VERSION 5.7 ;
  NOWIREEXTENSIONATPIN ON ;
  DIVIDERCHAR "/" ;
  BUSBITCHARS "[]" ;
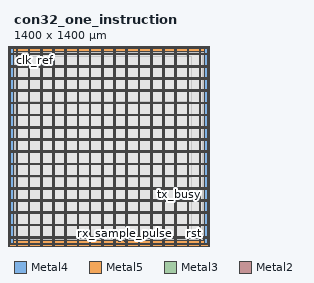
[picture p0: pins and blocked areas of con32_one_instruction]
MACRO con32_one_instruction
  CLASS BLOCK ;
  FOREIGN con32_one_instruction ;
  ORIGIN 0.000 0.000 ;
  SIZE 1400.000 BY 1400.000 ;
  PIN VDD
    DIRECTION INOUT ;
    USE POWER ;
    PORT
      LAYER Metal4 ;
        RECT -24.880 -18.160 -4.880 1417.600 ;
    END
    PORT
      LAYER Metal4 ;
        RECT 1404.880 -18.160 1424.880 1417.600 ;
    END
    PORT
      LAYER Metal5 ;
        RECT -24.880 -18.160 1424.880 1.840 ;
    END
    PORT
      LAYER Metal5 ;
        RECT -24.880 1397.600 1424.880 1417.600 ;
    END
    PORT
      LAYER Metal4 ;
        RECT 14.940 -42.960 19.940 1442.400 ;
    END
    PORT
      LAYER Metal4 ;
        RECT 104.940 -42.960 109.940 1442.400 ;
    END
    PORT
      LAYER Metal4 ;
        RECT 194.940 -42.960 199.940 1442.400 ;
    END
    PORT
      LAYER Metal4 ;
        RECT 284.940 -42.960 289.940 1442.400 ;
    END
    PORT
      LAYER Metal4 ;
        RECT 374.940 -42.960 379.940 1442.400 ;
    END
    PORT
      LAYER Metal4 ;
        RECT 464.940 -42.960 469.940 1442.400 ;
    END
    PORT
      LAYER Metal4 ;
        RECT 554.940 -42.960 559.940 1442.400 ;
    END
    PORT
      LAYER Metal4 ;
        RECT 644.940 -42.960 649.940 1442.400 ;
    END
    PORT
      LAYER Metal4 ;
        RECT 734.940 -42.960 739.940 1442.400 ;
    END
    PORT
      LAYER Metal4 ;
        RECT 824.940 -42.960 829.940 1442.400 ;
    END
    PORT
      LAYER Metal4 ;
        RECT 914.940 -42.960 919.940 1442.400 ;
    END
    PORT
      LAYER Metal4 ;
        RECT 1004.940 -42.960 1009.940 1442.400 ;
    END
    PORT
      LAYER Metal4 ;
        RECT 1094.940 -42.960 1099.940 1442.400 ;
    END
    PORT
      LAYER Metal4 ;
        RECT 1184.940 -42.960 1189.940 1442.400 ;
    END
    PORT
      LAYER Metal4 ;
        RECT 1274.940 -42.960 1279.940 1442.400 ;
    END
    PORT
      LAYER Metal4 ;
        RECT 1364.940 -42.960 1369.940 1442.400 ;
    END
    PORT
      LAYER Metal5 ;
        RECT -49.680 21.990 1449.680 26.990 ;
    END
    PORT
      LAYER Metal5 ;
        RECT -49.680 111.990 1449.680 116.990 ;
    END
    PORT
      LAYER Metal5 ;
        RECT -49.680 201.990 1449.680 206.990 ;
    END
    PORT
      LAYER Metal5 ;
        RECT -49.680 291.990 1449.680 296.990 ;
    END
    PORT
      LAYER Metal5 ;
        RECT -49.680 381.990 1449.680 386.990 ;
    END
    PORT
      LAYER Metal5 ;
        RECT -49.680 471.990 1449.680 476.990 ;
    END
    PORT
      LAYER Metal5 ;
        RECT -49.680 561.990 1449.680 566.990 ;
    END
    PORT
      LAYER Metal5 ;
        RECT -49.680 651.990 1449.680 656.990 ;
    END
    PORT
      LAYER Metal5 ;
        RECT -49.680 741.990 1449.680 746.990 ;
    END
    PORT
      LAYER Metal5 ;
        RECT -49.680 831.990 1449.680 836.990 ;
    END
    PORT
      LAYER Metal5 ;
        RECT -49.680 921.990 1449.680 926.990 ;
    END
    PORT
      LAYER Metal5 ;
        RECT -49.680 1011.990 1449.680 1016.990 ;
    END
    PORT
      LAYER Metal5 ;
        RECT -49.680 1101.990 1449.680 1106.990 ;
    END
    PORT
      LAYER Metal5 ;
        RECT -49.680 1191.990 1449.680 1196.990 ;
    END
    PORT
      LAYER Metal5 ;
        RECT -49.680 1281.990 1449.680 1286.990 ;
    END
    PORT
      LAYER Metal5 ;
        RECT -49.680 1371.990 1449.680 1376.990 ;
    END
  END VDD
  PIN VSS
    DIRECTION INOUT ;
    USE GROUND ;
    PORT
      LAYER Metal4 ;
        RECT -49.680 -42.960 -29.680 1442.400 ;
    END
    PORT
      LAYER Metal4 ;
        RECT 1429.680 -42.960 1449.680 1442.400 ;
    END
    PORT
      LAYER Metal5 ;
        RECT -49.680 -42.960 1449.680 -22.960 ;
    END
    PORT
      LAYER Metal5 ;
        RECT -49.680 1422.400 1449.680 1442.400 ;
    END
    PORT
      LAYER Metal4 ;
        RECT 21.940 -42.960 26.940 1442.400 ;
    END
    PORT
      LAYER Metal4 ;
        RECT 111.940 -42.960 116.940 1442.400 ;
    END
    PORT
      LAYER Metal4 ;
        RECT 201.940 -42.960 206.940 1442.400 ;
    END
    PORT
      LAYER Metal4 ;
        RECT 291.940 -42.960 296.940 1442.400 ;
    END
    PORT
      LAYER Metal4 ;
        RECT 381.940 -42.960 386.940 1442.400 ;
    END
    PORT
      LAYER Metal4 ;
        RECT 471.940 -42.960 476.940 1442.400 ;
    END
    PORT
      LAYER Metal4 ;
        RECT 561.940 -42.960 566.940 1442.400 ;
    END
    PORT
      LAYER Metal4 ;
        RECT 651.940 -42.960 656.940 1442.400 ;
    END
    PORT
      LAYER Metal4 ;
        RECT 741.940 -42.960 746.940 1442.400 ;
    END
    PORT
      LAYER Metal4 ;
        RECT 831.940 -42.960 836.940 1442.400 ;
    END
    PORT
      LAYER Metal4 ;
        RECT 921.940 -42.960 926.940 1442.400 ;
    END
    PORT
      LAYER Metal4 ;
        RECT 1011.940 -42.960 1016.940 1442.400 ;
    END
    PORT
      LAYER Metal4 ;
        RECT 1101.940 -42.960 1106.940 1442.400 ;
    END
    PORT
      LAYER Metal4 ;
        RECT 1191.940 -42.960 1196.940 1442.400 ;
    END
    PORT
      LAYER Metal4 ;
        RECT 1281.940 -42.960 1286.940 1442.400 ;
    END
    PORT
      LAYER Metal4 ;
        RECT 1371.940 -42.960 1376.940 1442.400 ;
    END
    PORT
      LAYER Metal5 ;
        RECT -49.680 28.990 1449.680 33.990 ;
    END
    PORT
      LAYER Metal5 ;
        RECT -49.680 118.990 1449.680 123.990 ;
    END
    PORT
      LAYER Metal5 ;
        RECT -49.680 208.990 1449.680 213.990 ;
    END
    PORT
      LAYER Metal5 ;
        RECT -49.680 298.990 1449.680 303.990 ;
    END
    PORT
      LAYER Metal5 ;
        RECT -49.680 388.990 1449.680 393.990 ;
    END
    PORT
      LAYER Metal5 ;
        RECT -49.680 478.990 1449.680 483.990 ;
    END
    PORT
      LAYER Metal5 ;
        RECT -49.680 568.990 1449.680 573.990 ;
    END
    PORT
      LAYER Metal5 ;
        RECT -49.680 658.990 1449.680 663.990 ;
    END
    PORT
      LAYER Metal5 ;
        RECT -49.680 748.990 1449.680 753.990 ;
    END
    PORT
      LAYER Metal5 ;
        RECT -49.680 838.990 1449.680 843.990 ;
    END
    PORT
      LAYER Metal5 ;
        RECT -49.680 928.990 1449.680 933.990 ;
    END
    PORT
      LAYER Metal5 ;
        RECT -49.680 1018.990 1449.680 1023.990 ;
    END
    PORT
      LAYER Metal5 ;
        RECT -49.680 1108.990 1449.680 1113.990 ;
    END
    PORT
      LAYER Metal5 ;
        RECT -49.680 1198.990 1449.680 1203.990 ;
    END
    PORT
      LAYER Metal5 ;
        RECT -49.680 1288.990 1449.680 1293.990 ;
    END
    PORT
      LAYER Metal5 ;
        RECT -49.680 1378.990 1449.680 1383.990 ;
    END
  END VSS
  PIN clk_ref
    DIRECTION INPUT ;
    USE SIGNAL ;
    ANTENNAGATEAREA 2.369000 ;
    PORT
      LAYER Metal3 ;
        RECT 0.000 1370.880 0.560 1371.440 ;
    END
  END clk_ref
  PIN rst
    DIRECTION INPUT ;
    USE SIGNAL ;
    ANTENNAGATEAREA 0.498500 ;
    PORT
      LAYER Metal3 ;
        RECT 1399.440 14.560 1400.000 15.120 ;
    END
  END rst
  PIN rx_sample_pulse
    DIRECTION OUTPUT ;
    USE SIGNAL ;
    ANTENNADIFFAREA 1.986000 ;
    PORT
      LAYER Metal2 ;
        RECT 814.240 0.000 814.800 0.560 ;
    END
  END rx_sample_pulse
  PIN rxd
    DIRECTION INPUT ;
    USE SIGNAL ;
    ANTENNAGATEAREA 0.396000 ;
    PORT
      LAYER Metal2 ;
        RECT 770.560 0.000 771.120 0.560 ;
    END
  END rxd
  PIN rxd_out
    DIRECTION OUTPUT ;
    USE SIGNAL ;
    ANTENNADIFFAREA 1.986000 ;
    PORT
      LAYER Metal2 ;
        RECT 780.640 0.000 781.200 0.560 ;
    END
  END rxd_out
  PIN tx_busy
    DIRECTION OUTPUT ;
    USE SIGNAL ;
    PORT
      LAYER Metal3 ;
        RECT 1399.440 342.720 1400.000 343.280 ;
    END
  END tx_busy
  PIN txd
    DIRECTION OUTPUT ;
    USE SIGNAL ;
    PORT
      LAYER Metal3 ;
        RECT 1399.440 328.160 1400.000 328.720 ;
    END
  END txd
  OBS
      LAYER Nwell ;
        RECT 0.690 7.410 1400.000 1392.030 ;
        RECT 1415.810 331.040 1424.510 333.630 ;
      LAYER Pwell ;
        RECT 1415.810 328.850 1424.510 331.040 ;
      LAYER Nwell ;
        RECT 1405.730 252.640 1414.430 255.230 ;
      LAYER Pwell ;
        RECT 1405.730 250.450 1414.430 252.640 ;
        RECT 1420.850 45.280 1429.550 47.470 ;
      LAYER Nwell ;
        RECT 1420.850 42.690 1429.550 45.280 ;
      LAYER Metal1 ;
        RECT 1.120 7.540 1400.000 1391.900 ;
        RECT 1416.240 332.900 1424.080 333.500 ;
        RECT 1416.805 332.010 1417.035 332.900 ;
        RECT 1417.925 331.960 1418.155 332.670 ;
        RECT 1419.045 332.330 1419.275 332.900 ;
        RECT 1420.065 331.960 1420.295 332.670 ;
        RECT 1421.465 332.440 1421.695 332.900 ;
        RECT 1422.585 332.100 1422.815 332.670 ;
        RECT 1423.605 332.480 1423.835 332.900 ;
        RECT 1417.480 331.640 1420.295 331.960 ;
        RECT 1420.895 331.870 1422.815 332.100 ;
        RECT 1417.480 330.790 1417.800 331.640 ;
        RECT 1420.895 331.320 1421.125 331.870 ;
        RECT 1418.135 331.020 1421.125 331.320 ;
        RECT 1421.740 331.020 1423.460 331.400 ;
        RECT 1417.480 330.560 1420.295 330.790 ;
        RECT 1416.650 329.580 1416.990 330.265 ;
        RECT 1417.825 329.970 1418.055 330.560 ;
        RECT 1418.890 329.580 1419.230 330.265 ;
        RECT 1420.065 329.970 1420.295 330.560 ;
        RECT 1420.895 330.780 1421.125 331.020 ;
        RECT 1420.895 330.550 1422.715 330.780 ;
        RECT 1421.130 329.580 1421.470 330.265 ;
        RECT 1422.485 329.970 1422.715 330.550 ;
        RECT 1423.550 329.580 1423.890 330.265 ;
        RECT 1416.240 328.980 1424.080 329.580 ;
        RECT 1406.160 254.500 1414.000 255.100 ;
        RECT 1406.725 253.610 1406.955 254.500 ;
        RECT 1407.845 253.560 1408.075 254.270 ;
        RECT 1408.965 253.930 1409.195 254.500 ;
        RECT 1409.985 253.560 1410.215 254.270 ;
        RECT 1411.385 254.040 1411.615 254.500 ;
        RECT 1412.505 253.700 1412.735 254.270 ;
        RECT 1413.525 254.080 1413.755 254.500 ;
        RECT 1407.400 253.240 1410.215 253.560 ;
        RECT 1410.815 253.470 1412.735 253.700 ;
        RECT 1407.400 252.390 1407.720 253.240 ;
        RECT 1410.815 252.920 1411.045 253.470 ;
        RECT 1408.055 252.620 1411.045 252.920 ;
        RECT 1411.660 252.620 1413.380 253.000 ;
        RECT 1407.400 252.160 1410.215 252.390 ;
        RECT 1406.570 251.180 1406.910 251.865 ;
        RECT 1407.745 251.570 1407.975 252.160 ;
        RECT 1408.810 251.180 1409.150 251.865 ;
        RECT 1409.985 251.570 1410.215 252.160 ;
        RECT 1410.815 252.380 1411.045 252.620 ;
        RECT 1410.815 252.150 1412.635 252.380 ;
        RECT 1411.050 251.180 1411.390 251.865 ;
        RECT 1412.405 251.570 1412.635 252.150 ;
        RECT 1413.470 251.180 1413.810 251.865 ;
        RECT 1406.160 250.580 1414.000 251.180 ;
        RECT 1421.280 46.740 1429.120 47.340 ;
        RECT 1421.690 46.055 1422.030 46.740 ;
        RECT 1422.865 45.760 1423.095 46.350 ;
        RECT 1423.930 46.055 1424.270 46.740 ;
        RECT 1425.105 45.760 1425.335 46.350 ;
        RECT 1426.170 46.055 1426.510 46.740 ;
        RECT 1427.525 45.770 1427.755 46.350 ;
        RECT 1428.590 46.055 1428.930 46.740 ;
        RECT 1422.520 45.530 1425.335 45.760 ;
        RECT 1425.935 45.540 1427.755 45.770 ;
        RECT 1422.520 44.680 1422.840 45.530 ;
        RECT 1425.935 45.300 1426.165 45.540 ;
        RECT 1423.175 45.000 1426.165 45.300 ;
        RECT 1422.520 44.360 1425.335 44.680 ;
        RECT 1421.845 43.420 1422.075 44.310 ;
        RECT 1422.965 43.650 1423.195 44.360 ;
        RECT 1424.085 43.420 1424.315 43.990 ;
        RECT 1425.105 43.650 1425.335 44.360 ;
        RECT 1425.935 44.450 1426.165 45.000 ;
        RECT 1426.780 44.920 1428.500 45.300 ;
        RECT 1425.935 44.220 1427.855 44.450 ;
        RECT 1426.505 43.420 1426.735 43.880 ;
        RECT 1427.625 43.650 1427.855 44.220 ;
        RECT 1428.645 43.420 1428.875 43.840 ;
        RECT 1421.280 42.820 1429.120 43.420 ;
      LAYER Metal2 ;
        RECT 2.380 0.860 1398.180 1391.790 ;
        RECT 2.380 0.560 770.260 0.860 ;
        RECT 771.420 0.560 780.340 0.860 ;
        RECT 781.500 0.560 813.940 0.860 ;
        RECT 815.100 0.560 1398.180 0.860 ;
      LAYER Metal3 ;
        RECT 0.560 1371.740 1399.440 1391.740 ;
        RECT 0.860 1370.580 1399.440 1371.740 ;
        RECT 0.560 343.580 1399.440 1370.580 ;
        RECT 0.560 342.420 1399.140 343.580 ;
        RECT 0.560 329.020 1399.440 342.420 ;
        RECT 0.560 327.860 1399.140 329.020 ;
        RECT 0.560 15.420 1399.440 327.860 ;
        RECT 0.560 14.260 1399.140 15.420 ;
        RECT 0.560 6.300 1399.440 14.260 ;
      LAYER Metal4 ;
        RECT 7.980 8.360 14.640 1388.710 ;
        RECT 20.240 8.360 21.640 1388.710 ;
        RECT 27.240 8.360 104.640 1388.710 ;
        RECT 110.240 8.360 111.640 1388.710 ;
        RECT 117.240 8.360 194.640 1388.710 ;
        RECT 200.240 8.360 201.640 1388.710 ;
        RECT 207.240 8.360 284.640 1388.710 ;
        RECT 290.240 8.360 291.640 1388.710 ;
        RECT 297.240 8.360 374.640 1388.710 ;
        RECT 380.240 8.360 381.640 1388.710 ;
        RECT 387.240 8.360 464.640 1388.710 ;
        RECT 470.240 8.360 471.640 1388.710 ;
        RECT 477.240 8.360 554.640 1388.710 ;
        RECT 560.240 8.360 561.640 1388.710 ;
        RECT 567.240 8.360 644.640 1388.710 ;
        RECT 650.240 8.360 651.640 1388.710 ;
        RECT 657.240 8.360 734.640 1388.710 ;
        RECT 740.240 8.360 741.640 1388.710 ;
        RECT 747.240 8.360 824.640 1388.710 ;
        RECT 830.240 8.360 831.640 1388.710 ;
        RECT 837.240 8.360 914.640 1388.710 ;
        RECT 920.240 8.360 921.640 1388.710 ;
        RECT 927.240 8.360 1004.640 1388.710 ;
        RECT 1010.240 8.360 1011.640 1388.710 ;
        RECT 1017.240 8.360 1094.640 1388.710 ;
        RECT 1100.240 8.360 1101.640 1388.710 ;
        RECT 1107.240 8.360 1184.640 1388.710 ;
        RECT 1190.240 8.360 1191.640 1388.710 ;
        RECT 1197.240 8.360 1274.640 1388.710 ;
        RECT 1280.240 8.360 1281.640 1388.710 ;
        RECT 1287.240 8.360 1364.640 1388.710 ;
        RECT 1370.240 8.360 1371.640 1388.710 ;
        RECT 1377.240 8.360 1385.860 1388.710 ;
      LAYER Metal5 ;
        RECT 10.140 1294.590 1310.340 1357.870 ;
        RECT 10.140 1287.590 1310.340 1288.390 ;
        RECT 10.140 1204.590 1310.340 1281.390 ;
        RECT 10.140 1197.590 1310.340 1198.390 ;
        RECT 10.140 1114.590 1310.340 1191.390 ;
        RECT 10.140 1107.590 1310.340 1108.390 ;
        RECT 10.140 1024.590 1310.340 1101.390 ;
        RECT 10.140 1017.590 1310.340 1018.390 ;
        RECT 10.140 934.590 1310.340 1011.390 ;
        RECT 10.140 927.590 1310.340 928.390 ;
        RECT 10.140 844.590 1310.340 921.390 ;
        RECT 10.140 837.590 1310.340 838.390 ;
        RECT 10.140 754.590 1310.340 831.390 ;
        RECT 10.140 747.590 1310.340 748.390 ;
        RECT 10.140 664.590 1310.340 741.390 ;
        RECT 10.140 657.590 1310.340 658.390 ;
        RECT 10.140 574.590 1310.340 651.390 ;
        RECT 10.140 567.590 1310.340 568.390 ;
        RECT 10.140 484.590 1310.340 561.390 ;
        RECT 10.140 477.590 1310.340 478.390 ;
        RECT 10.140 394.590 1310.340 471.390 ;
        RECT 10.140 387.590 1310.340 388.390 ;
        RECT 10.140 304.590 1310.340 381.390 ;
        RECT 10.140 297.590 1310.340 298.390 ;
        RECT 10.140 214.590 1310.340 291.390 ;
        RECT 10.140 207.590 1310.340 208.390 ;
        RECT 10.140 124.590 1310.340 201.390 ;
        RECT 10.140 117.590 1310.340 118.390 ;
        RECT 10.140 34.590 1310.340 111.390 ;
        RECT 10.140 27.590 1310.340 28.390 ;
        RECT 10.140 8.330 1310.340 21.390 ;
  END
END con32_one_instruction
END LIBRARY

